One B-rep face of a CAD part: STEP entity #5440.
In plain terms, the planar face has unit normal (0, 0, -1).
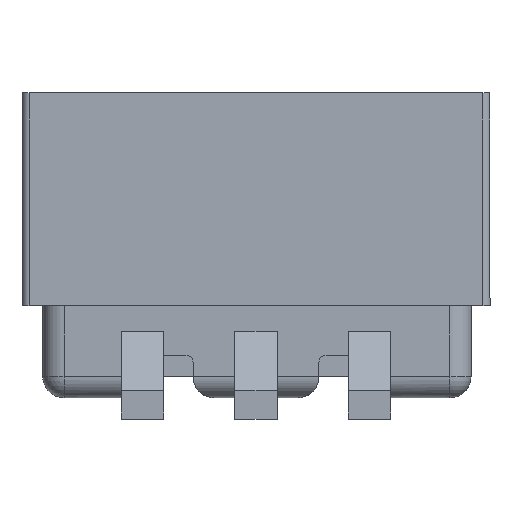
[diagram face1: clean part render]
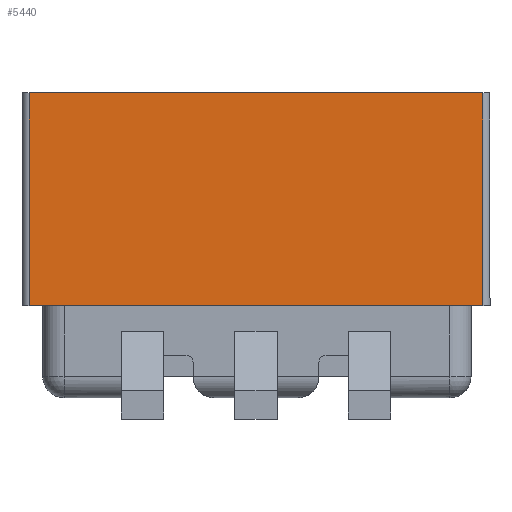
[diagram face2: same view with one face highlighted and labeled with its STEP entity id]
Its self-contained STEP definition (entity closure, numbers rounded to 3 decimals):
#2576 = PLANE('',#2577);
#2577 = AXIS2_PLACEMENT_3D('',#2578,#2579,#2580);
#2578 = CARTESIAN_POINT('',(7.293,0.,
    -11.303));
#2579 = DIRECTION('',(0.,1.,0.));
#2580 = DIRECTION('',(0.,0.,1.));
#4776 = VERTEX_POINT('',#4777);
#4777 = CARTESIAN_POINT('',(4.093,0.,
    -15.103));
#4796 = CYLINDRICAL_SURFACE('',#4797,0.1);
#4797 = AXIS2_PLACEMENT_3D('',#4798,#4799,#4800);
#4798 = CARTESIAN_POINT('',(4.093,3.,
    -15.003));
#4799 = DIRECTION('',(0.,1.,0.));
#4800 = DIRECTION('',(0.,0.,1.));
#4808 = EDGE_CURVE('',#4776,#4809,#4811,.T.);
#4809 = VERTEX_POINT('',#4810);
#4810 = CARTESIAN_POINT('',(10.493,0.,
    -15.103));
#4811 = SURFACE_CURVE('',#4812,(#4816,#4823),.PCURVE_S1.);
#4812 = LINE('',#4813,#4814);
#4813 = CARTESIAN_POINT('',(3.993,0.,
    -15.103));
#4814 = VECTOR('',#4815,1.);
#4815 = DIRECTION('',(1.,0.,0.));
#4816 = PCURVE('',#2576,#4817);
#4817 = DEFINITIONAL_REPRESENTATION('',(#4818),#4822);
#4818 = LINE('',#4819,#4820);
#4819 = CARTESIAN_POINT('',(-3.8,-3.3));
#4820 = VECTOR('',#4821,1.);
#4821 = DIRECTION('',(0.,1.));
#4822 = ( GEOMETRIC_REPRESENTATION_CONTEXT(2) 
PARAMETRIC_REPRESENTATION_CONTEXT() REPRESENTATION_CONTEXT('2D SPACE',''
  ) );
#4823 = PCURVE('',#4824,#4829);
#4824 = PLANE('',#4825);
#4825 = AXIS2_PLACEMENT_3D('',#4826,#4827,#4828);
#4826 = CARTESIAN_POINT('',(3.993,3.,
    -15.103));
#4827 = DIRECTION('',(0.,0.,-1.));
#4828 = DIRECTION('',(-1.,0.,0.));
#4829 = DEFINITIONAL_REPRESENTATION('',(#4830),#4834);
#4830 = LINE('',#4831,#4832);
#4831 = CARTESIAN_POINT('',(-0.,-3.));
#4832 = VECTOR('',#4833,1.);
#4833 = DIRECTION('',(-1.,0.));
#4834 = ( GEOMETRIC_REPRESENTATION_CONTEXT(2) 
PARAMETRIC_REPRESENTATION_CONTEXT() REPRESENTATION_CONTEXT('2D SPACE',''
  ) );
#4855 = CYLINDRICAL_SURFACE('',#4856,0.1);
#4856 = AXIS2_PLACEMENT_3D('',#4857,#4858,#4859);
#4857 = CARTESIAN_POINT('',(10.493,3.,
    -15.003));
#4858 = DIRECTION('',(0.,-1.,0.));
#4859 = DIRECTION('',(0.,0.,-1.));
#5266 = PLANE('',#5267);
#5267 = AXIS2_PLACEMENT_3D('',#5268,#5269,#5270);
#5268 = CARTESIAN_POINT('',(7.293,3.,
    -11.303));
#5269 = DIRECTION('',(0.,1.,0.));
#5270 = DIRECTION('',(0.,0.,1.));
#5440 = ADVANCED_FACE('',(#5441),#4824,.T.);
#5441 = FACE_BOUND('',#5442,.T.);
#5442 = EDGE_LOOP('',(#5443,#5468,#5489,#5490));
#5443 = ORIENTED_EDGE('',*,*,#5444,.T.);
#5444 = EDGE_CURVE('',#5445,#5447,#5449,.T.);
#5445 = VERTEX_POINT('',#5446);
#5446 = CARTESIAN_POINT('',(4.093,3.,
    -15.103));
#5447 = VERTEX_POINT('',#5448);
#5448 = CARTESIAN_POINT('',(10.493,3.,
    -15.103));
#5449 = SURFACE_CURVE('',#5450,(#5454,#5461),.PCURVE_S1.);
#5450 = LINE('',#5451,#5452);
#5451 = CARTESIAN_POINT('',(3.993,3.,
    -15.103));
#5452 = VECTOR('',#5453,1.);
#5453 = DIRECTION('',(1.,0.,0.));
#5454 = PCURVE('',#4824,#5455);
#5455 = DEFINITIONAL_REPRESENTATION('',(#5456),#5460);
#5456 = LINE('',#5457,#5458);
#5457 = CARTESIAN_POINT('',(0.,0.));
#5458 = VECTOR('',#5459,1.);
#5459 = DIRECTION('',(-1.,0.));
#5460 = ( GEOMETRIC_REPRESENTATION_CONTEXT(2) 
PARAMETRIC_REPRESENTATION_CONTEXT() REPRESENTATION_CONTEXT('2D SPACE',''
  ) );
#5461 = PCURVE('',#5266,#5462);
#5462 = DEFINITIONAL_REPRESENTATION('',(#5463),#5467);
#5463 = LINE('',#5464,#5465);
#5464 = CARTESIAN_POINT('',(-3.8,-3.3));
#5465 = VECTOR('',#5466,1.);
#5466 = DIRECTION('',(0.,1.));
#5467 = ( GEOMETRIC_REPRESENTATION_CONTEXT(2) 
PARAMETRIC_REPRESENTATION_CONTEXT() REPRESENTATION_CONTEXT('2D SPACE',''
  ) );
#5468 = ORIENTED_EDGE('',*,*,#5469,.T.);
#5469 = EDGE_CURVE('',#5447,#4809,#5470,.T.);
#5470 = SURFACE_CURVE('',#5471,(#5475,#5482),.PCURVE_S1.);
#5471 = LINE('',#5472,#5473);
#5472 = CARTESIAN_POINT('',(10.493,3.,
    -15.103));
#5473 = VECTOR('',#5474,1.);
#5474 = DIRECTION('',(0.,-1.,0.));
#5475 = PCURVE('',#4824,#5476);
#5476 = DEFINITIONAL_REPRESENTATION('',(#5477),#5481);
#5477 = LINE('',#5478,#5479);
#5478 = CARTESIAN_POINT('',(-6.5,0.));
#5479 = VECTOR('',#5480,1.);
#5480 = DIRECTION('',(0.,-1.));
#5481 = ( GEOMETRIC_REPRESENTATION_CONTEXT(2) 
PARAMETRIC_REPRESENTATION_CONTEXT() REPRESENTATION_CONTEXT('2D SPACE',''
  ) );
#5482 = PCURVE('',#4855,#5483);
#5483 = DEFINITIONAL_REPRESENTATION('',(#5484),#5488);
#5484 = LINE('',#5485,#5486);
#5485 = CARTESIAN_POINT('',(0.,0.));
#5486 = VECTOR('',#5487,1.);
#5487 = DIRECTION('',(0.,1.));
#5488 = ( GEOMETRIC_REPRESENTATION_CONTEXT(2) 
PARAMETRIC_REPRESENTATION_CONTEXT() REPRESENTATION_CONTEXT('2D SPACE',''
  ) );
#5489 = ORIENTED_EDGE('',*,*,#4808,.F.);
#5490 = ORIENTED_EDGE('',*,*,#5491,.T.);
#5491 = EDGE_CURVE('',#4776,#5445,#5492,.T.);
#5492 = SURFACE_CURVE('',#5493,(#5497,#5504),.PCURVE_S1.);
#5493 = LINE('',#5494,#5495);
#5494 = CARTESIAN_POINT('',(4.093,3.,
    -15.103));
#5495 = VECTOR('',#5496,1.);
#5496 = DIRECTION('',(0.,1.,0.));
#5497 = PCURVE('',#4824,#5498);
#5498 = DEFINITIONAL_REPRESENTATION('',(#5499),#5503);
#5499 = LINE('',#5500,#5501);
#5500 = CARTESIAN_POINT('',(-0.1,0.));
#5501 = VECTOR('',#5502,1.);
#5502 = DIRECTION('',(0.,1.));
#5503 = ( GEOMETRIC_REPRESENTATION_CONTEXT(2) 
PARAMETRIC_REPRESENTATION_CONTEXT() REPRESENTATION_CONTEXT('2D SPACE',''
  ) );
#5504 = PCURVE('',#4796,#5505);
#5505 = DEFINITIONAL_REPRESENTATION('',(#5506),#5510);
#5506 = LINE('',#5507,#5508);
#5507 = CARTESIAN_POINT('',(3.142,0.));
#5508 = VECTOR('',#5509,1.);
#5509 = DIRECTION('',(0.,1.));
#5510 = ( GEOMETRIC_REPRESENTATION_CONTEXT(2) 
PARAMETRIC_REPRESENTATION_CONTEXT() REPRESENTATION_CONTEXT('2D SPACE',''
  ) );
